One B-rep face of a CAD part: STEP entity #184.
In plain terms, the planar face has unit normal (1, 0, 0).
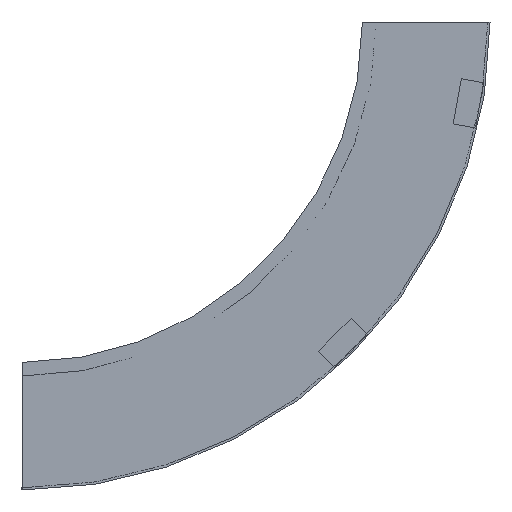
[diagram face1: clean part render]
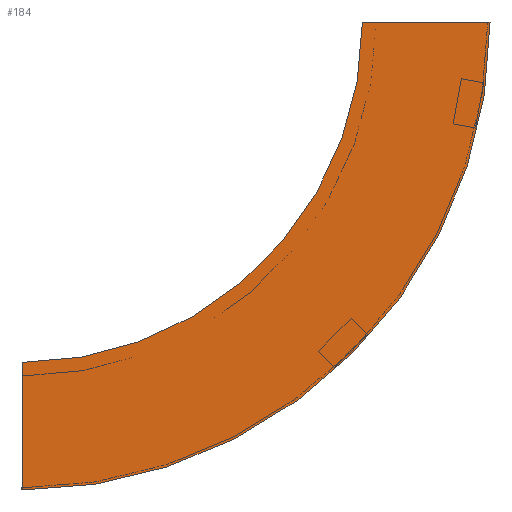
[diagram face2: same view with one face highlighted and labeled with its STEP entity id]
Its self-contained STEP definition (entity closure, numbers rounded to 3 decimals):
#4 = VERTEX_POINT ( 'NONE', #435 ) ;
#7 = PLANE ( 'NONE',  #452 ) ;
#17 = CARTESIAN_POINT ( 'NONE',  ( 0., 300., -300. ) ) ;
#25 = EDGE_CURVE ( 'NONE', #491, #321, #266, .T. ) ;
#32 = VECTOR ( 'NONE', #35, 1000. ) ;
#35 = DIRECTION ( 'NONE',  ( 0., 0., 1. ) ) ;
#54 = DIRECTION ( 'NONE',  ( 1., 0., 0. ) ) ;
#75 = CARTESIAN_POINT ( 'NONE',  ( 0., 300., 0. ) ) ;
#77 = CARTESIAN_POINT ( 'NONE',  ( 0., 0., 0. ) ) ;
#118 = DIRECTION ( 'NONE',  ( 0., 0., 1. ) ) ;
#124 = LINE ( 'NONE', #159, #127 ) ;
#127 = VECTOR ( 'NONE', #432, 1000. ) ;
#148 = ORIENTED_EDGE ( 'NONE', *, *, #25, .F. ) ;
#155 = DIRECTION ( 'NONE',  ( -1., 0., 0. ) ) ;
#159 = CARTESIAN_POINT ( 'NONE',  ( 0., -112.5, 0. ) ) ;
#161 = FACE_OUTER_BOUND ( 'NONE', #295, .T. ) ;
#162 = ORIENTED_EDGE ( 'NONE', *, *, #181, .T. ) ;
#164 = AXIS2_PLACEMENT_3D ( 'NONE', #75, #169, #344 ) ;
#169 = DIRECTION ( 'NONE',  ( 1., 0., 0. ) ) ;
#181 = EDGE_CURVE ( 'NONE', #4, #376, #519, .T. ) ;
#184 = ADVANCED_FACE ( 'NONE', ( #161 ), #7, .F. ) ;
#195 = ORIENTED_EDGE ( 'NONE', *, *, #354, .T. ) ;
#239 = ORIENTED_EDGE ( 'NONE', *, *, #533, .F. ) ;
#258 = LINE ( 'NONE', #431, #32 ) ;
#266 = CIRCLE ( 'NONE', #164, 300. ) ;
#295 = EDGE_LOOP ( 'NONE', ( #148, #239, #162, #195 ) ) ;
#321 = VERTEX_POINT ( 'NONE', #17 ) ;
#344 = DIRECTION ( 'NONE',  ( 0., -1., 0. ) ) ;
#354 = EDGE_CURVE ( 'NONE', #376, #321, #258, .T. ) ;
#376 = VERTEX_POINT ( 'NONE', #479 ) ;
#381 = AXIS2_PLACEMENT_3D ( 'NONE', #503, #54, #547 ) ;
#431 = CARTESIAN_POINT ( 'NONE',  ( 0., 300., -412.5 ) ) ;
#432 = DIRECTION ( 'NONE',  ( 0., 1., 0. ) ) ;
#435 = CARTESIAN_POINT ( 'NONE',  ( 0., -112.5, 0. ) ) ;
#452 = AXIS2_PLACEMENT_3D ( 'NONE', #511, #155, #118 ) ;
#479 = CARTESIAN_POINT ( 'NONE',  ( 0., 300., -412.5 ) ) ;
#491 = VERTEX_POINT ( 'NONE', #77 ) ;
#503 = CARTESIAN_POINT ( 'NONE',  ( 0., 300., 0. ) ) ;
#511 = CARTESIAN_POINT ( 'NONE',  ( 0., -112.5, 0. ) ) ;
#519 = CIRCLE ( 'NONE', #381, 412.5 ) ;
#533 = EDGE_CURVE ( 'NONE', #4, #491, #124, .T. ) ;
#547 = DIRECTION ( 'NONE',  ( 0., -1., 0. ) ) ;
